VERSION 5.7 ;
  NOWIREEXTENSIONATPIN ON ;
  DIVIDERCHAR "/" ;
  BUSBITCHARS "[]" ;
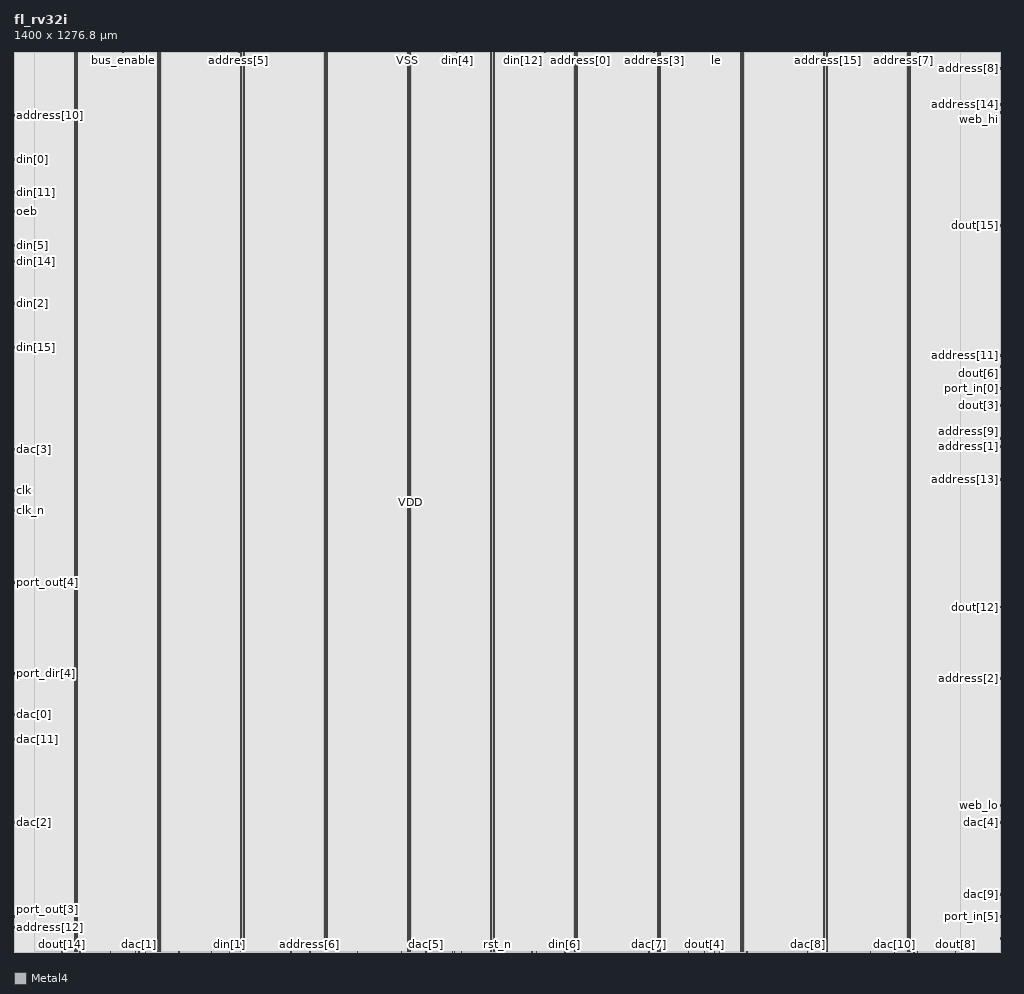
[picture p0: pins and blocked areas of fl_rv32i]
MACRO fl_rv32i
  CLASS BLOCK ;
  FOREIGN fl_rv32i ;
  ORIGIN 0.000 0.000 ;
  SIZE 1400.000 BY 1276.800 ;
  PIN VSS
    DIRECTION INOUT ;
    USE GROUND ;
    PORT
      LAYER Metal4 ;
        RECT 85.540 1.400 86.940 1275.400 ;
    END
    PORT
      LAYER Metal4 ;
        RECT 203.700 1.400 205.100 1275.400 ;
    END
    PORT
      LAYER Metal4 ;
        RECT 321.860 1.400 323.260 1275.400 ;
    END
    PORT
      LAYER Metal4 ;
        RECT 440.020 1.400 441.420 1275.400 ;
    END
    PORT
      LAYER Metal4 ;
        RECT 558.180 1.400 559.580 1275.400 ;
    END
    PORT
      LAYER Metal4 ;
        RECT 676.340 1.400 677.740 1275.400 ;
    END
    PORT
      LAYER Metal4 ;
        RECT 794.500 1.400 795.900 1275.400 ;
    END
    PORT
      LAYER Metal4 ;
        RECT 912.660 1.400 914.060 1275.400 ;
    END
    PORT
      LAYER Metal4 ;
        RECT 1030.820 1.400 1032.220 1275.400 ;
    END
    PORT
      LAYER Metal4 ;
        RECT 1148.980 1.400 1150.380 1275.400 ;
    END
    PORT
      LAYER Metal4 ;
        RECT 1267.140 1.400 1268.540 1275.400 ;
    END
  END VSS
  PIN VDD
    DIRECTION INOUT ;
    USE POWER ;
    PORT
      LAYER Metal4 ;
        RECT 88.900 1.400 90.300 1275.400 ;
    END
    PORT
      LAYER Metal4 ;
        RECT 207.060 1.400 208.460 1275.400 ;
    END
    PORT
      LAYER Metal4 ;
        RECT 325.220 1.400 326.620 1275.400 ;
    END
    PORT
      LAYER Metal4 ;
        RECT 443.380 1.400 444.780 1275.400 ;
    END
    PORT
      LAYER Metal4 ;
        RECT 561.540 1.400 562.940 1275.400 ;
    END
    PORT
      LAYER Metal4 ;
        RECT 679.700 1.400 681.100 1275.400 ;
    END
    PORT
      LAYER Metal4 ;
        RECT 797.860 1.400 799.260 1275.400 ;
    END
    PORT
      LAYER Metal4 ;
        RECT 916.020 1.400 917.420 1275.400 ;
    END
    PORT
      LAYER Metal4 ;
        RECT 1034.180 1.400 1035.580 1275.400 ;
    END
    PORT
      LAYER Metal4 ;
        RECT 1152.340 1.400 1153.740 1275.400 ;
    END
    PORT
      LAYER Metal4 ;
        RECT 1270.500 1.400 1271.900 1275.400 ;
    END
  END VDD
  PIN port_dir[0]
    DIRECTION OUTPUT ;
    USE SIGNAL ;
    ANTENNADIFFAREA 8.338300 ;
    PORT
      LAYER Metal4 ;
        RECT 171.920 0.000 172.480 0.560 ;
    END
  END port_dir[0]
  PIN web_hi
    DIRECTION OUTPUT ;
    USE SIGNAL ;
    ANTENNADIFFAREA 8.338300 ;
    PORT
      LAYER Metal4 ;
        RECT 1399.440 1189.720 1400.000 1192.520 ;
    END
  END web_hi
  PIN web_lo
    DIRECTION OUTPUT ;
    USE SIGNAL ;
    ANTENNADIFFAREA 8.338300 ;
    PORT
      LAYER Metal4 ;
        RECT 1399.440 205.800 1400.000 208.600 ;
    END
  END web_lo
  PIN bus_enable
    DIRECTION OUTPUT ;
    USE SIGNAL ;
    ANTENNADIFFAREA 8.338300 ;
    PORT
      LAYER Metal4 ;
        RECT 154.560 1276.240 155.120 1276.800 ;
    END
  END bus_enable
  PIN oeb
    DIRECTION OUTPUT ;
    USE SIGNAL ;
    ANTENNADIFFAREA 8.338300 ;
    PORT
      LAYER Metal4 ;
        RECT 0.000 1048.600 0.560 1051.400 ;
    END
  END oeb
  PIN dout[0]
    DIRECTION OUTPUT ;
    USE SIGNAL ;
    ANTENNADIFFAREA 8.338300 ;
    PORT
      LAYER Metal4 ;
        RECT 486.640 0.000 487.200 0.560 ;
    END
  END dout[0]
  PIN dout[1]
    DIRECTION OUTPUT ;
    USE SIGNAL ;
    ANTENNADIFFAREA 8.338300 ;
    PORT
      LAYER Metal4 ;
        RECT 1292.480 1276.240 1293.040 1276.800 ;
    END
  END dout[1]
  PIN dout[2]
    DIRECTION OUTPUT ;
    USE SIGNAL ;
    ANTENNADIFFAREA 8.338300 ;
    PORT
      LAYER Metal4 ;
        RECT 549.360 0.000 549.920 0.560 ;
    END
  END dout[2]
  PIN dout[3]
    DIRECTION OUTPUT ;
    USE SIGNAL ;
    ANTENNADIFFAREA 8.338300 ;
    PORT
      LAYER Metal4 ;
        RECT 1399.440 774.200 1400.000 777.000 ;
    END
  END dout[3]
  PIN dout[4]
    DIRECTION OUTPUT ;
    USE SIGNAL ;
    ANTENNADIFFAREA 8.338300 ;
    PORT
      LAYER Metal4 ;
        RECT 979.440 0.000 980.000 0.560 ;
    END
  END dout[4]
  PIN dout[5]
    DIRECTION OUTPUT ;
    USE SIGNAL ;
    ANTENNADIFFAREA 8.338300 ;
    PORT
      LAYER Metal4 ;
        RECT 956.480 0.000 957.040 0.560 ;
    END
  END dout[5]
  PIN dout[6]
    DIRECTION OUTPUT ;
    USE SIGNAL ;
    ANTENNADIFFAREA 8.338300 ;
    PORT
      LAYER Metal4 ;
        RECT 1399.440 829.080 1400.000 831.880 ;
    END
  END dout[6]
  PIN dout[7]
    DIRECTION OUTPUT ;
    USE SIGNAL ;
    ANTENNADIFFAREA 8.338300 ;
    PORT
      LAYER Metal4 ;
        RECT 993.440 0.000 994.000 0.560 ;
    END
  END dout[7]
  PIN dout[15]
    DIRECTION OUTPUT ;
    USE SIGNAL ;
    ANTENNADIFFAREA 8.338300 ;
    PORT
      LAYER Metal4 ;
        RECT 1399.440 1029.000 1400.000 1031.800 ;
    END
  END dout[15]
  PIN dout[14]
    DIRECTION OUTPUT ;
    USE SIGNAL ;
    ANTENNADIFFAREA 8.338300 ;
    PORT
      LAYER Metal4 ;
        RECT 67.760 0.000 68.320 0.560 ;
    END
  END dout[14]
  PIN dout[13]
    DIRECTION OUTPUT ;
    USE SIGNAL ;
    ANTENNADIFFAREA 8.338300 ;
    PORT
      LAYER Metal4 ;
        RECT 1285.760 1276.240 1286.320 1276.800 ;
    END
  END dout[13]
  PIN dout[12]
    DIRECTION OUTPUT ;
    USE SIGNAL ;
    ANTENNADIFFAREA 8.338300 ;
    PORT
      LAYER Metal4 ;
        RECT 1399.440 488.040 1400.000 490.840 ;
    END
  END dout[12]
  PIN dout[11]
    DIRECTION OUTPUT ;
    USE SIGNAL ;
    ANTENNADIFFAREA 8.338300 ;
    PORT
      LAYER Metal4 ;
        RECT 1282.400 1276.240 1282.960 1276.800 ;
    END
  END dout[11]
  PIN dout[9]
    DIRECTION OUTPUT ;
    USE SIGNAL ;
    ANTENNADIFFAREA 8.338300 ;
    PORT
      LAYER Metal4 ;
        RECT 1000.160 0.000 1000.720 0.560 ;
    END
  END dout[9]
  PIN dout[8]
    DIRECTION OUTPUT ;
    USE SIGNAL ;
    ANTENNADIFFAREA 8.338300 ;
    PORT
      LAYER Metal4 ;
        RECT 1335.040 0.000 1335.600 0.560 ;
    END
  END dout[8]
  PIN dout[10]
    DIRECTION OUTPUT ;
    USE SIGNAL ;
    ANTENNADIFFAREA 8.338300 ;
    PORT
      LAYER Metal4 ;
        RECT 1214.640 0.000 1215.200 0.560 ;
    END
  END dout[10]
  PIN port_out[0]
    DIRECTION OUTPUT ;
    USE SIGNAL ;
    ANTENNADIFFAREA 8.338300 ;
    PORT
      LAYER Metal4 ;
        RECT 280.000 0.000 280.560 0.560 ;
    END
  END port_out[0]
  PIN port_out[3]
    DIRECTION OUTPUT ;
    USE SIGNAL ;
    ANTENNADIFFAREA 8.338300 ;
    PORT
      LAYER Metal4 ;
        RECT 0.000 49.000 0.560 51.800 ;
    END
  END port_out[3]
  PIN port_dir[1]
    DIRECTION OUTPUT ;
    USE SIGNAL ;
    ANTENNADIFFAREA 8.338300 ;
    PORT
      LAYER Metal4 ;
        RECT 392.560 0.000 393.120 0.560 ;
    END
  END port_dir[1]
  PIN port_dir[3]
    DIRECTION OUTPUT ;
    USE SIGNAL ;
    ANTENNADIFFAREA 8.338300 ;
    PORT
      LAYER Metal4 ;
        RECT 753.200 1276.240 753.760 1276.800 ;
    END
  END port_dir[3]
  PIN dac[0]
    DIRECTION OUTPUT ;
    USE SIGNAL ;
    ANTENNADIFFAREA 8.338300 ;
    PORT
      LAYER Metal4 ;
        RECT 0.000 335.160 0.560 337.960 ;
    END
  END dac[0]
  PIN dac[1]
    DIRECTION OUTPUT ;
    USE SIGNAL ;
    ANTENNADIFFAREA 8.338300 ;
    PORT
      LAYER Metal4 ;
        RECT 176.960 0.000 177.520 0.560 ;
    END
  END dac[1]
  PIN dac[2]
    DIRECTION OUTPUT ;
    USE SIGNAL ;
    ANTENNADIFFAREA 8.338300 ;
    PORT
      LAYER Metal4 ;
        RECT 0.000 182.280 0.560 185.080 ;
    END
  END dac[2]
  PIN dac[11]
    DIRECTION OUTPUT ;
    USE SIGNAL ;
    ANTENNADIFFAREA 8.338300 ;
    PORT
      LAYER Metal4 ;
        RECT 0.000 299.880 0.560 302.680 ;
    END
  END dac[11]
  PIN dac[10]
    DIRECTION OUTPUT ;
    USE SIGNAL ;
    ANTENNADIFFAREA 8.338300 ;
    PORT
      LAYER Metal4 ;
        RECT 1248.800 0.000 1249.360 0.560 ;
    END
  END dac[10]
  PIN dac[9]
    DIRECTION OUTPUT ;
    USE SIGNAL ;
    ANTENNADIFFAREA 8.338300 ;
    PORT
      LAYER Metal4 ;
        RECT 1399.440 80.360 1400.000 83.160 ;
    END
  END dac[9]
  PIN dac[8]
    DIRECTION OUTPUT ;
    USE SIGNAL ;
    ANTENNADIFFAREA 8.338300 ;
    PORT
      LAYER Metal4 ;
        RECT 1125.600 0.000 1126.160 0.560 ;
    END
  END dac[8]
  PIN dac[7]
    DIRECTION OUTPUT ;
    USE SIGNAL ;
    ANTENNADIFFAREA 8.338300 ;
    PORT
      LAYER Metal4 ;
        RECT 900.480 0.000 901.040 0.560 ;
    END
  END dac[7]
  PIN dac[6]
    DIRECTION OUTPUT ;
    USE SIGNAL ;
    ANTENNADIFFAREA 8.338300 ;
    PORT
      LAYER Metal4 ;
        RECT 691.040 0.000 691.600 0.560 ;
    END
  END dac[6]
  PIN dac[5]
    DIRECTION OUTPUT ;
    USE SIGNAL ;
    ANTENNADIFFAREA 8.338300 ;
    PORT
      LAYER Metal4 ;
        RECT 584.080 0.000 584.640 0.560 ;
    END
  END dac[5]
  PIN dac[4]
    DIRECTION OUTPUT ;
    USE SIGNAL ;
    ANTENNADIFFAREA 8.338300 ;
    PORT
      LAYER Metal4 ;
        RECT 1399.440 182.280 1400.000 185.080 ;
    END
  END dac[4]
  PIN dac[3]
    DIRECTION OUTPUT ;
    USE SIGNAL ;
    ANTENNADIFFAREA 8.338300 ;
    PORT
      LAYER Metal4 ;
        RECT 0.000 711.480 0.560 714.280 ;
    END
  END dac[3]
  PIN port_dir[5]
    DIRECTION OUTPUT ;
    USE SIGNAL ;
    ANTENNADIFFAREA 8.338300 ;
    PORT
      LAYER Metal4 ;
        RECT 233.520 0.000 234.080 0.560 ;
    END
  END port_dir[5]
  PIN port_dir[4]
    DIRECTION OUTPUT ;
    USE SIGNAL ;
    ANTENNADIFFAREA 8.338300 ;
    PORT
      LAYER Metal4 ;
        RECT 0.000 393.960 0.560 396.760 ;
    END
  END port_dir[4]
  PIN port_dir[2]
    DIRECTION OUTPUT ;
    USE SIGNAL ;
    ANTENNADIFFAREA 8.338300 ;
    PORT
      LAYER Metal4 ;
        RECT 93.520 0.000 94.080 0.560 ;
    END
  END port_dir[2]
  PIN address[14]
    DIRECTION OUTPUT ;
    USE SIGNAL ;
    ANTENNADIFFAREA 8.338300 ;
    PORT
      LAYER Metal4 ;
        RECT 1399.440 1201.480 1400.000 1204.280 ;
    END
  END address[14]
  PIN address[9]
    DIRECTION OUTPUT ;
    USE SIGNAL ;
    ANTENNADIFFAREA 8.338300 ;
    PORT
      LAYER Metal4 ;
        RECT 1399.440 727.160 1400.000 729.960 ;
    END
  END address[9]
  PIN address[15]
    DIRECTION OUTPUT ;
    USE SIGNAL ;
    ANTENNADIFFAREA 8.338300 ;
    PORT
      LAYER Metal4 ;
        RECT 1154.720 1276.240 1155.280 1276.800 ;
    END
  END address[15]
  PIN address[13]
    DIRECTION OUTPUT ;
    USE SIGNAL ;
    ANTENNADIFFAREA 8.338300 ;
    PORT
      LAYER Metal4 ;
        RECT 1399.440 668.360 1400.000 671.160 ;
    END
  END address[13]
  PIN address[10]
    DIRECTION OUTPUT ;
    USE SIGNAL ;
    ANTENNADIFFAREA 8.338300 ;
    PORT
      LAYER Metal4 ;
        RECT 0.000 1185.800 0.560 1188.600 ;
    END
  END address[10]
  PIN address[8]
    DIRECTION OUTPUT ;
    USE SIGNAL ;
    ANTENNADIFFAREA 8.338300 ;
    PORT
      LAYER Metal4 ;
        RECT 1399.440 1252.440 1400.000 1255.240 ;
    END
  END address[8]
  PIN address[2]
    DIRECTION OUTPUT ;
    USE SIGNAL ;
    ANTENNADIFFAREA 8.338300 ;
    PORT
      LAYER Metal4 ;
        RECT 1399.440 386.120 1400.000 388.920 ;
    END
  END address[2]
  PIN address[7]
    DIRECTION OUTPUT ;
    USE SIGNAL ;
    ANTENNADIFFAREA 8.338300 ;
    PORT
      LAYER Metal4 ;
        RECT 1261.680 1276.240 1262.240 1276.800 ;
    END
  END address[7]
  PIN address[12]
    DIRECTION OUTPUT ;
    USE SIGNAL ;
    ANTENNADIFFAREA 8.338300 ;
    PORT
      LAYER Metal4 ;
        RECT 0.000 33.320 0.560 36.120 ;
    END
  END address[12]
  PIN address[11]
    DIRECTION OUTPUT ;
    USE SIGNAL ;
    ANTENNADIFFAREA 8.338300 ;
    PORT
      LAYER Metal4 ;
        RECT 1399.440 844.760 1400.000 847.560 ;
    END
  END address[11]
  PIN address[6]
    DIRECTION OUTPUT ;
    USE SIGNAL ;
    ANTENNADIFFAREA 8.338300 ;
    PORT
      LAYER Metal4 ;
        RECT 419.440 0.000 420.000 0.560 ;
    END
  END address[6]
  PIN address[0]
    DIRECTION OUTPUT ;
    USE SIGNAL ;
    ANTENNADIFFAREA 8.338300 ;
    PORT
      LAYER Metal4 ;
        RECT 803.600 1276.240 804.160 1276.800 ;
    END
  END address[0]
  PIN address[4]
    DIRECTION OUTPUT ;
    USE SIGNAL ;
    ANTENNADIFFAREA 8.338300 ;
    PORT
      LAYER Metal4 ;
        RECT 740.880 0.000 741.440 0.560 ;
    END
  END address[4]
  PIN address[5]
    DIRECTION OUTPUT ;
    USE SIGNAL ;
    ANTENNADIFFAREA 8.338300 ;
    PORT
      LAYER Metal4 ;
        RECT 318.640 1276.240 319.200 1276.800 ;
    END
  END address[5]
  PIN address[1]
    DIRECTION OUTPUT ;
    USE SIGNAL ;
    ANTENNADIFFAREA 8.338300 ;
    PORT
      LAYER Metal4 ;
        RECT 1399.440 715.400 1400.000 718.200 ;
    END
  END address[1]
  PIN address[3]
    DIRECTION OUTPUT ;
    USE SIGNAL ;
    ANTENNADIFFAREA 8.338300 ;
    PORT
      LAYER Metal4 ;
        RECT 907.760 1276.240 908.320 1276.800 ;
    END
  END address[3]
  PIN port_out[5]
    DIRECTION OUTPUT ;
    USE SIGNAL ;
    ANTENNADIFFAREA 8.338300 ;
    PORT
      LAYER Metal4 ;
        RECT 136.640 0.000 137.200 0.560 ;
    END
  END port_out[5]
  PIN port_out[2]
    DIRECTION OUTPUT ;
    USE SIGNAL ;
    ANTENNADIFFAREA 8.338300 ;
    PORT
      LAYER Metal4 ;
        RECT 622.160 0.000 622.720 0.560 ;
    END
  END port_out[2]
  PIN port_out[4]
    DIRECTION OUTPUT ;
    USE SIGNAL ;
    ANTENNADIFFAREA 8.338300 ;
    PORT
      LAYER Metal4 ;
        RECT 0.000 523.320 0.560 526.120 ;
    END
  END port_out[4]
  PIN port_out[1]
    DIRECTION OUTPUT ;
    USE SIGNAL ;
    ANTENNADIFFAREA 8.338300 ;
    PORT
      LAYER Metal4 ;
        RECT 624.960 0.000 625.520 0.560 ;
    END
  END port_out[1]
  PIN le
    DIRECTION OUTPUT ;
    USE SIGNAL ;
    ANTENNADIFFAREA 8.338300 ;
    PORT
      LAYER Metal4 ;
        RECT 996.240 1276.240 996.800 1276.800 ;
    END
  END le
  PIN port_in[4]
    DIRECTION INPUT ;
    USE SIGNAL ;
    ANTENNAGATEAREA 1.999200 ;
    ANTENNADIFFAREA 0.877000 ;
    PORT
      LAYER Metal4 ;
        RECT 1039.360 0.000 1039.920 0.560 ;
    END
  END port_in[4]
  PIN port_in[3]
    DIRECTION INPUT ;
    USE SIGNAL ;
    ANTENNAGATEAREA 1.999200 ;
    ANTENNADIFFAREA 0.877000 ;
    PORT
      LAYER Metal4 ;
        RECT 1281.280 0.000 1281.840 0.560 ;
    END
  END port_in[3]
  PIN din[2]
    DIRECTION INPUT ;
    USE SIGNAL ;
    ANTENNAGATEAREA 1.999200 ;
    ANTENNADIFFAREA 0.877000 ;
    PORT
      LAYER Metal4 ;
        RECT 0.000 919.240 0.560 922.040 ;
    END
  END din[2]
  PIN din[5]
    DIRECTION INPUT ;
    USE SIGNAL ;
    ANTENNAGATEAREA 1.999200 ;
    ANTENNADIFFAREA 0.877000 ;
    PORT
      LAYER Metal4 ;
        RECT 0.000 1001.560 0.560 1004.360 ;
    END
  END din[5]
  PIN din[11]
    DIRECTION INPUT ;
    USE SIGNAL ;
    ANTENNAGATEAREA 1.999200 ;
    ANTENNADIFFAREA 0.877000 ;
    PORT
      LAYER Metal4 ;
        RECT 0.000 1076.040 0.560 1078.840 ;
    END
  END din[11]
  PIN din[14]
    DIRECTION INPUT ;
    USE SIGNAL ;
    ANTENNAGATEAREA 1.999200 ;
    ANTENNADIFFAREA 0.877000 ;
    PORT
      LAYER Metal4 ;
        RECT 0.000 978.040 0.560 980.840 ;
    END
  END din[14]
  PIN din[15]
    DIRECTION INPUT ;
    USE SIGNAL ;
    ANTENNAGATEAREA 1.999200 ;
    ANTENNADIFFAREA 0.877000 ;
    PORT
      LAYER Metal4 ;
        RECT 0.000 856.520 0.560 859.320 ;
    END
  END din[15]
  PIN din[0]
    DIRECTION INPUT ;
    USE SIGNAL ;
    ANTENNAGATEAREA 1.999200 ;
    ANTENNADIFFAREA 0.877000 ;
    PORT
      LAYER Metal4 ;
        RECT 0.000 1123.080 0.560 1125.880 ;
    END
  END din[0]
  PIN din[8]
    DIRECTION INPUT ;
    USE SIGNAL ;
    ANTENNAGATEAREA 1.999200 ;
    ANTENNADIFFAREA 0.877000 ;
    PORT
      LAYER Metal4 ;
        RECT 837.200 1276.240 837.760 1276.800 ;
    END
  END din[8]
  PIN din[12]
    DIRECTION INPUT ;
    USE SIGNAL ;
    ANTENNAGATEAREA 1.999200 ;
    ANTENNADIFFAREA 0.877000 ;
    PORT
      LAYER Metal4 ;
        RECT 721.280 1276.240 721.840 1276.800 ;
    END
  END din[12]
  PIN din[13]
    DIRECTION INPUT ;
    USE SIGNAL ;
    ANTENNAGATEAREA 1.999200 ;
    ANTENNADIFFAREA 0.877000 ;
    PORT
      LAYER Metal4 ;
        RECT 954.800 1276.240 955.360 1276.800 ;
    END
  END din[13]
  PIN din[1]
    DIRECTION INPUT ;
    USE SIGNAL ;
    ANTENNAGATEAREA 1.999200 ;
    ANTENNADIFFAREA 0.877000 ;
    PORT
      LAYER Metal4 ;
        RECT 305.200 0.000 305.760 0.560 ;
    END
  END din[1]
  PIN din[6]
    DIRECTION INPUT ;
    USE SIGNAL ;
    ANTENNAGATEAREA 1.999200 ;
    ANTENNADIFFAREA 0.877000 ;
    PORT
      LAYER Metal4 ;
        RECT 781.200 0.000 781.760 0.560 ;
    END
  END din[6]
  PIN port_in[5]
    DIRECTION INPUT ;
    USE SIGNAL ;
    ANTENNAGATEAREA 1.999200 ;
    ANTENNADIFFAREA 0.877000 ;
    PORT
      LAYER Metal4 ;
        RECT 1399.440 49.000 1400.000 51.800 ;
    END
  END port_in[5]
  PIN din[9]
    DIRECTION INPUT ;
    USE SIGNAL ;
    ANTENNAGATEAREA 1.999200 ;
    ANTENNADIFFAREA 0.877000 ;
    PORT
      LAYER Metal4 ;
        RECT 734.720 0.000 735.280 0.560 ;
    END
  END din[9]
  PIN din[3]
    DIRECTION INPUT ;
    USE SIGNAL ;
    ANTENNAGATEAREA 1.999200 ;
    ANTENNADIFFAREA 0.877000 ;
    PORT
      LAYER Metal4 ;
        RECT 185.920 0.000 186.480 0.560 ;
    END
  END din[3]
  PIN port_in[1]
    DIRECTION INPUT ;
    USE SIGNAL ;
    ANTENNAGATEAREA 1.999200 ;
    ANTENNADIFFAREA 0.877000 ;
    PORT
      LAYER Metal4 ;
        RECT 1399.440 17.640 1400.000 20.440 ;
    END
  END port_in[1]
  PIN port_in[2]
    DIRECTION INPUT ;
    USE SIGNAL ;
    ANTENNAGATEAREA 1.999200 ;
    ANTENNADIFFAREA 0.877000 ;
    PORT
      LAYER Metal4 ;
        RECT 1276.240 0.000 1276.800 0.560 ;
    END
  END port_in[2]
  PIN rst_n
    DIRECTION INPUT ;
    USE SIGNAL ;
    ANTENNAGATEAREA 2.665600 ;
    ANTENNADIFFAREA 0.438500 ;
    PORT
      LAYER Metal4 ;
        RECT 686.000 0.000 686.560 0.560 ;
    END
  END rst_n
  PIN din[4]
    DIRECTION INPUT ;
    USE SIGNAL ;
    ANTENNAGATEAREA 1.999200 ;
    ANTENNADIFFAREA 0.877000 ;
    PORT
      LAYER Metal4 ;
        RECT 628.320 1276.240 628.880 1276.800 ;
    END
  END din[4]
  PIN din[10]
    DIRECTION INPUT ;
    USE SIGNAL ;
    ANTENNAGATEAREA 1.999200 ;
    ANTENNADIFFAREA 0.438500 ;
    PORT
      LAYER Metal4 ;
        RECT 634.480 0.000 635.040 0.560 ;
    END
  END din[10]
  PIN din[7]
    DIRECTION INPUT ;
    USE SIGNAL ;
    ANTENNAGATEAREA 1.999200 ;
    ANTENNADIFFAREA 0.877000 ;
    PORT
      LAYER Metal4 ;
        RECT 589.120 1276.240 589.680 1276.800 ;
    END
  END din[7]
  PIN port_in[0]
    DIRECTION INPUT ;
    USE SIGNAL ;
    ANTENNAGATEAREA 1.999200 ;
    ANTENNADIFFAREA 0.877000 ;
    PORT
      LAYER Metal4 ;
        RECT 1399.440 797.720 1400.000 800.520 ;
    END
  END port_in[0]
  PIN clk
    DIRECTION INPUT ;
    USE SIGNAL ;
    ANTENNAGATEAREA 2.352000 ;
    ANTENNADIFFAREA 0.877000 ;
    PORT
      LAYER Metal4 ;
        RECT 0.000 652.680 0.560 655.480 ;
    END
  END clk
  PIN clk_n
    DIRECTION INPUT ;
    USE SIGNAL ;
    ANTENNAGATEAREA 2.352000 ;
    ANTENNADIFFAREA 0.877000 ;
    PORT
      LAYER Metal4 ;
        RECT 0.000 625.240 0.560 628.040 ;
    END
  END clk_n
  OBS
      LAYER Nwell ;
        RECT 0.970 0.970 1399.030 1275.830 ;
      LAYER Metal1 ;
        RECT 1.400 1.100 1398.600 1275.700 ;
      LAYER Metal2 ;
        RECT 0.000 0.000 1400.000 1276.720 ;
      LAYER Metal3 ;
        RECT 0.000 0.000 1400.000 1276.720 ;
      LAYER Metal4 ;
        RECT 28.980 1275.940 154.260 1276.240 ;
        RECT 155.420 1275.940 318.340 1276.240 ;
        RECT 319.500 1275.940 588.820 1276.240 ;
        RECT 589.980 1275.940 628.020 1276.240 ;
        RECT 629.180 1275.940 720.980 1276.240 ;
        RECT 722.140 1275.940 752.900 1276.240 ;
        RECT 754.060 1275.940 803.300 1276.240 ;
        RECT 804.460 1275.940 836.900 1276.240 ;
        RECT 838.060 1275.940 907.460 1276.240 ;
        RECT 908.620 1275.940 954.500 1276.240 ;
        RECT 955.660 1275.940 995.940 1276.240 ;
        RECT 997.100 1275.940 1154.420 1276.240 ;
        RECT 1155.580 1275.940 1261.380 1276.240 ;
        RECT 1262.540 1275.940 1282.100 1276.240 ;
        RECT 1283.260 1275.940 1285.460 1276.240 ;
        RECT 1286.620 1275.940 1292.180 1276.240 ;
        RECT 1293.340 1275.940 1343.020 1276.240 ;
        RECT 28.980 1275.700 1343.020 1275.940 ;
        RECT 28.980 1.120 85.240 1275.700 ;
        RECT 87.240 1.120 88.600 1275.700 ;
        RECT 90.600 1.120 203.400 1275.700 ;
        RECT 205.400 1.120 206.760 1275.700 ;
        RECT 208.760 1.120 321.560 1275.700 ;
        RECT 323.560 1.120 324.920 1275.700 ;
        RECT 326.920 1.120 439.720 1275.700 ;
        RECT 441.720 1.120 443.080 1275.700 ;
        RECT 445.080 1.120 557.880 1275.700 ;
        RECT 559.880 1.120 561.240 1275.700 ;
        RECT 563.240 1.120 676.040 1275.700 ;
        RECT 678.040 1.120 679.400 1275.700 ;
        RECT 681.400 1.120 794.200 1275.700 ;
        RECT 796.200 1.120 797.560 1275.700 ;
        RECT 799.560 1.120 912.360 1275.700 ;
        RECT 914.360 1.120 915.720 1275.700 ;
        RECT 917.720 1.120 1030.520 1275.700 ;
        RECT 1032.520 1.120 1033.880 1275.700 ;
        RECT 1035.880 1.120 1148.680 1275.700 ;
        RECT 1150.680 1.120 1152.040 1275.700 ;
        RECT 1154.040 1.120 1266.840 1275.700 ;
        RECT 1268.840 1.120 1270.200 1275.700 ;
        RECT 1272.200 1.120 1343.020 1275.700 ;
  END
END fl_rv32i
END LIBRARY

